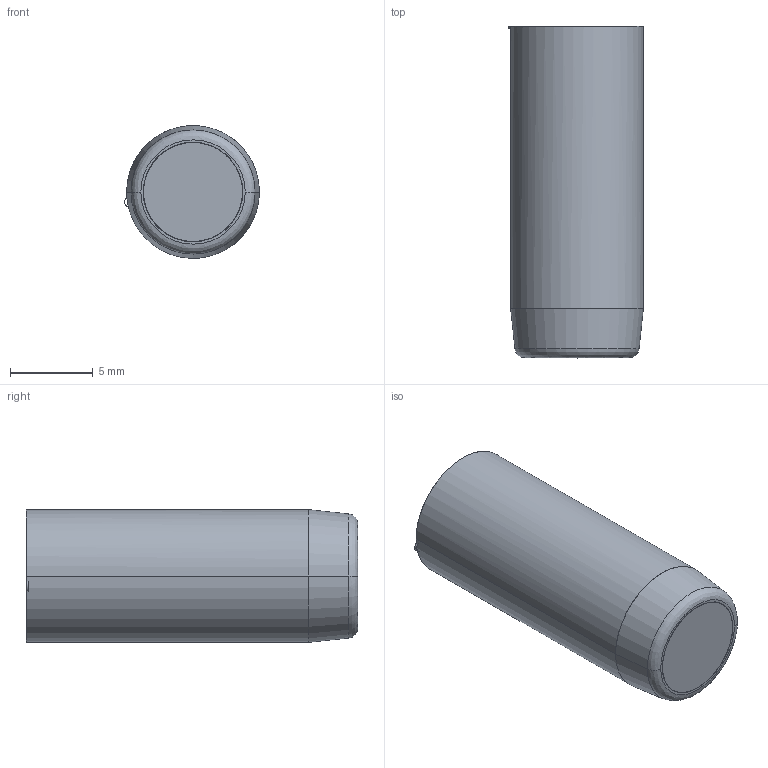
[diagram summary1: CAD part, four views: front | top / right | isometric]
IGES file: header records copied from the file, then geometry measured from it (millimetres).
Start section: START RECORD GO HERE.
Global section: file name: fa0847sf.igs; native system: DASSAULT SYSTEMES CATIA V5 R20 - www.3ds.com; preprocessor: CATIA Version 5 Release 20 ; author: Utente; organization: NB04-ASUS; date: 20201108.084142; units: millimetre
Bounding box: 8.12 x 20 x 8 mm (x, y, z)
Surface area: 1513.1 mm2 (no closed solid volume)
Topology: 0 solids, 0 shells, 404 faces, 1976 edges, 1969 vertices
Faces by surface type: revolution 189, plane 139, bspline 76
